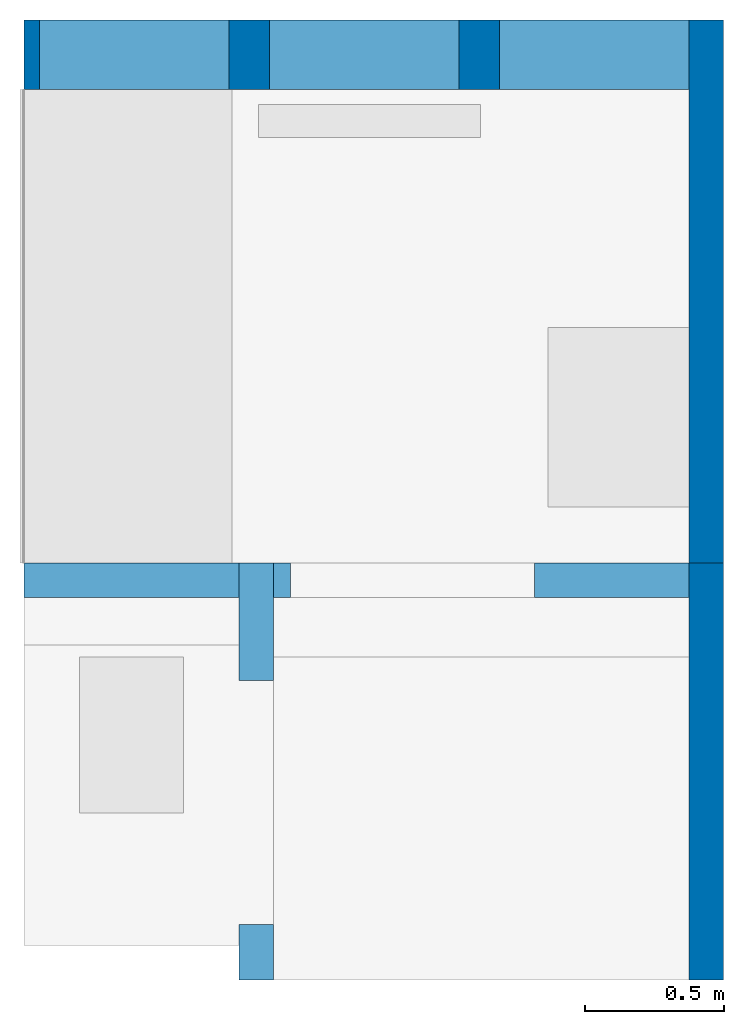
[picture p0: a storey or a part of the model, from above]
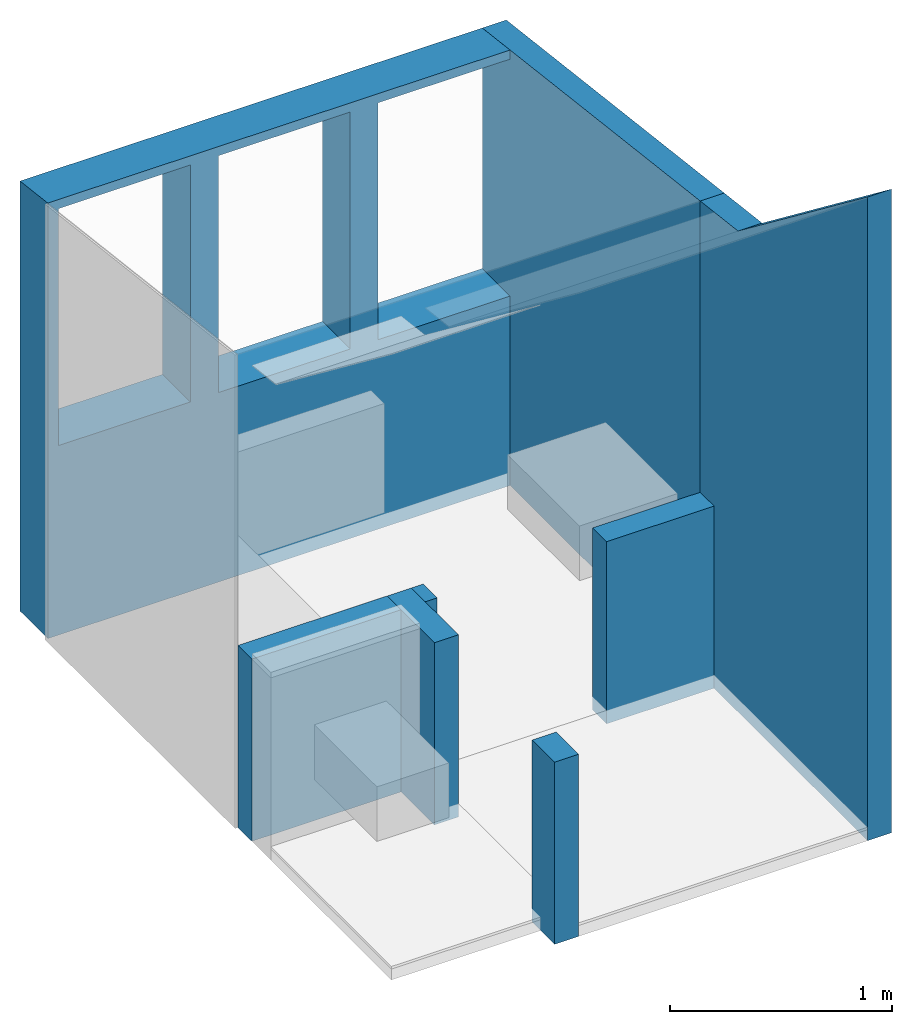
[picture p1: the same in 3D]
Properties of the parts of a building model (IFC4)

# File
Description: no view
File name: ÖBV_OEBV_Richtlinie_Einrichtung.ifc
Time: 2024-03-13T09:49:46
Author: Oesterreichische Bautechnik Vereinigung
Organization: OEBV
Written by: ODA SDAI 24.5
Authorization: OEBV

# IfcSite, Liegenschaft
RefLatitude: 48, 8, 10, 320000; RefLongitude: 11, 41, 19, 320000

# IfcBuildingStorey, Geschoss 01
In: Gebäude
Elevation: 0 m

# IfcSpace (3)
In: Geschoss 01
Name | Allright_Bauteil_ID
 | 0021Rau0000000123
 | 0021Rau0000000126
 | 0021Rau0000000128

# IfcBuildingElementProxy (3)
In: Geschoss 01
Name | Allright_Bauteil_ID

 | 0021ErE0000014534
 | 0021Inb0000000157 | Material: IW NFZ

# IfcCovering (15)
Name | In | PredefinedType | Material | Allright_Bauteil_ID
 | Geschoss 01 | FLOORING | Fliesen 0.03 m | 0021Bfl0000000022/01
 |  | CEILING | Putz 0.005 m | 0021Dfl0000000056/01
 |  | FLOORING | OSB Platte 0.06 m | 0021Bfl0000000057/01
 |  | FLOORING | Fliesen 0.014 m | 0021Bfl0000000057/02
 |  | SKIRTINGBOARD | SOL 20x70 Ei | 0021Lei0000000058
 |  | CEILING | Putz 0.005 m | 0021Dfl0000000051/01
 |  | FLOORING | OSB Platte 0.06 m | 0021Bfl0000000052/01
 |  | FLOORING | Fliesen 0.014 m | 0021Bfl0000000052/02
 |  | SKIRTINGBOARD | SOL 20x70 Ei | 0021Lei0000000053
 |  | CEILING | Putz 0.005 m | 0021Dfl0000000045/01
 |  | FLOORING | OSB Platte 0.06 m | 0021Bfl0000000046/01
 |  | FLOORING | Fliesen 0.014 m | 0021Bfl0000000046/02
 |  | SKIRTINGBOARD | SOL 20x70 Ei | 0021Lei0000000047
 |  | CLADDING | Putz 0.005 m | 0021Sfl0000000167/01
 |  | CLADDING | Fliesen 0.01 m | 0021Sfl0000000167/02

# IfcFurniture (4)
In: Geschoss 01
Name | Allright_Bauteil_ID
 | 0021ErE0000014318
 | 0021ErE0000014535
 | 0021ErE0000014536
 | 0021ErE0000000041

# IfcOpeningElement: Opening (5)
In: Geschoss 01
Name | Object Layer Attributes #1, Allright_Bauteil_ID
Türöffnung | AllplanAttributes - Allright_Bauteil_ID: 0021Tür0000000088
Türöffnung | AllplanAttributes - Allright_Bauteil_ID: 0021Tür0000000084
Fensteröffnung | 0021Fen0000000078
Fensteröffnung | 0021Fen0000000080
Fensteröffnung | 0021Fen0000000082

# IfcWall (6)
In: Geschoss 01
Material: NFZ
Name | Allright_Bauteil_ID
 | 0021Wa 0000000140
 | 0021Wa 0000000152
 | 0021Wa 0000000136
 | 0021Wa 0000000133
 | 0021Wa 0000000118
 | 0021Wa 0000000111
